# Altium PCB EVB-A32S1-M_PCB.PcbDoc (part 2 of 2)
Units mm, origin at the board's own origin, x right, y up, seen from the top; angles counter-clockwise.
Board outline 134 x 65 mm, 4 copper layers (L1 (Signal), L2 (GND), L3 (PWR), L4 (Signal)), stack 1.566 mm thick; 111 components, 86 nets, 414 pads, 364 vias.

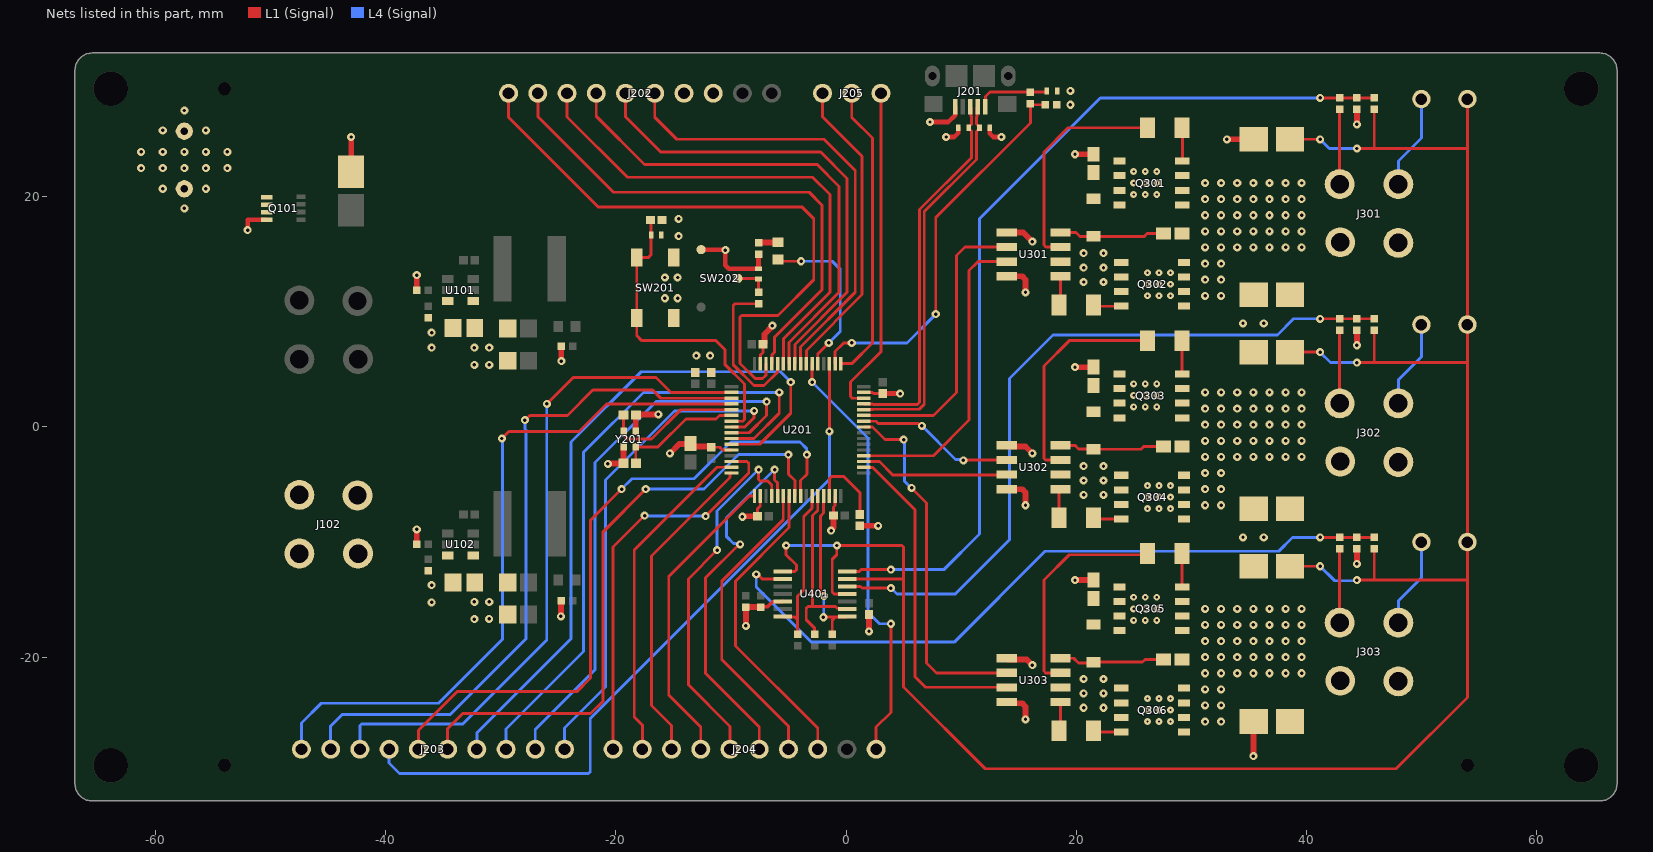
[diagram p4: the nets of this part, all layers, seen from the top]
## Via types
v1: diameter 0.7, hole 0.3, L1 (Signal) to L4 (Signal), tented both sides, 162 vias
v2: diameter 0.7, hole 0.3, L1 (Signal) to L4 (Signal), tented top, 144 vias
v3: diameter 0.6, hole 0.2, L1 (Signal) to L4 (Signal), tented top, 54 vias
v4: diameter 0.6, hole 0.2, L1 (Signal) to L4 (Signal), tented both sides, 4 vias

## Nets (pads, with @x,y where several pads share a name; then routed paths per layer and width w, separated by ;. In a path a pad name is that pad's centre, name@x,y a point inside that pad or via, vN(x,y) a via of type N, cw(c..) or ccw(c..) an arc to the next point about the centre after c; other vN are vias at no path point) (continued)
+VCC: C101.2 C105.2 C109.1 C301.2 C303.2 C305.2 D301.2 D302.2 D303.2 Q101.1 Q101.2 Q101.3 Q301.5 Q301.6 Q301.7 Q301.8 Q303.5 Q303.6 Q303.7 Q303.8 Q305.5 Q305.6 Q305.7 Q305.8 R101.2 R104.2 U101.3 U102.3 U301.1 U302.1 U303.1 | length 7.6
  L1 (Signal) w0.5: U303.1@13.96,-20.095 14.07,-20.205 15.705,-20.205 v1(16.2,-20.7) ; U302.1@13.96,-1.595 14.07,-1.705 15.605,-1.705 v1(16.2,-2.3) ; U301.1@13.96,16.905 15.395,16.905 v1(16.2,16.1)
  other v1: -36,-15.25 -36,-13.75 -36,6.9 -36,8.2 -57.5,19 -59.375,20.7 -55.625,20.7 -61.25,22.5 -59.375,22.5 -57.5,22.5 -55.625,22.5 -53.75,22.5 -61.25,23.9 -59.375,23.9 -57.5,23.9 -55.625,23.9 -53.75,23.9 -59.375,25.78 -55.625,25.78 -57.5,27.5
  other v3: 25,-16.8 26,-16.8 27,-16.8 25,-15.8 26,-15.8 27,-15.8 25,-14.8 26,-14.8 27,-14.8 25,1.75 26,1.75 27,1.75 25,2.75 26,2.75 27,2.75 25,3.75 26,3.75 27,3.75 25,20.2 26,20.2 27,20.2 25,21.2 26,21.2 27,21.2 25,22.2 26,22.2 27,22.2
BEMF_A: R406.2 R411.2 R412.1 U401.7 | length 78.9
  L1 (Signal) w0.25: U401.7@0.1,-12.55 1.154,-12.55 1.304,-12.4 v1(3.9,-12.4) ; v1(41.2,28.6) R412.1@42.9,28.6 R411.2@44.4,28.6 R406.2@45.9,28.6
  L4 (Signal) w0.25: v1(3.9,-12.4) 8.5,-12.4 11.6,-9.3 11.6,18.1 22.1,28.6 v1(41.2,28.6)
BEMF_B: R407.2 R410.2 R413.1 U401.5 | length 64.2
  L1 (Signal) w0.25: U401.5@0.1,-13.85 1.249,-13.85 1.399,-14 v1(3.9,-14) ; v1(41.2,9.4) R413.1@42.9,9.4 R410.2@44.4,9.4 R407.2@45.9,9.4
  L4 (Signal) w0.25: v1(3.9,-14) 3.925,-14 4.425,-14.5 9.5,-14.5 14.2,-9.8 14.2,4.2 18,8 37.5,8 38.9,9.4 v1(41.2,9.4)
BEMF_C: R408.2 R409.2 R414.1 U401.9 | length 63
  L1 (Signal) w0.25: v1(-7.8,-12.8) -7.678,-12.8 -7.278,-13.2 U401.9@-5.5,-13.2 ; v1(41.2,-9.6) R414.1@42.9,-9.6 ; R414.1@42.9,-9.6 R409.2@44.4,-9.6 R408.2@45.9,-9.6
  L4 (Signal) w0.25: v1(-7.8,-12.8) -7.8,-13.9 -3,-18.7 9.4,-18.7 17.3,-10.8 37.6,-10.8 38.8,-9.6 v1(41.2,-9.6)
BOOT0: R201.2 U201.60 | length 13.3
  L1 (Signal) w0.25: R201.2@-7.588,10.712 -9.654,10.712 -9.8,10.566 -9.8,5.4 -8,3.6 -7.112,3.6 -5.955,4.757 -5.955,5.495 U201.60@-5.95,5.5
COM: D401.1 D402.1 D403.1 R406.1 R407.1 R408.1 TP401.1 TP402.1 TP403.1 U401.4 U401.6 U401.8 | length 199.6
  L1 (Signal) w0.25: U401.8@-5.5,-12.55 -4.446,-12.55 -4.3,-12.404 -4.3,-12 -5.2,-11.1 v1(-5.2,-10.3) ; U401.4@0.1,-14.5 -1.054,-14.5 -1.2,-14.354 -1.2,-11.5 -0.8,-11.1 v1(-0.8,-10.3) 4.854,-10.3 5,-10.446 5,-13.2 5,-22.6 12.1,-29.7 47.8,-29.7 54,-23.5 54,-13.154 ; U401.6@0.1,-13.2 4.854,-13.2 4.954,-13.2 ; D403.1@38.575,-12.1 v1(41.2,-12.1) ; D402.1@38.575,6.5 v1(41.2,6.5) ; D401.1@38.575,25 v1(41.2,25) ; v1(44.4,-13.3) 45.9,-13.3 ; v1(44.4,5.6) 45.9,5.6 ; v1(44.4,24.2) 45.9,24.2 ; R408.1@45.9,-10.6 45.9,-13.3 ; R407.1@45.9,8.4 45.9,5.6 ; R406.1@45.9,27.6 45.9,24.2 ; TP403.1@54,28.5 54,24.2 ; 45.9,-13.3 53.854,-13.3 54,-13.154 ; 45.9,5.6 54,5.6 ; 45.9,24.2 54,24.2 ; 54,-13.154 TP401.1@54,-10 54,5.6 ; 54,5.6 TP402.1@54,8.9 54,24.2
  L4 (Signal) w0.25: v1(-5.2,-10.3) v1(-0.8,-10.3) ; v1(41.2,-12.1) 42.464,-13.364 44.336,-13.364 v1(44.4,-13.3) ; v1(41.2,6.5) 42.1,5.6 v1(44.4,5.6) ; v1(41.2,25) 42,24.2 v1(44.4,24.2)
GHO_A: Q301.4 R301.2 | length 2.9
  L1 (Signal) w0.25: Q301.4@29.235,23.105 R301.2@29.235,26
  L1 (Signal) w0.5: R301.2@29.2,26 R301.2@29.235,26
GHO_B: Q303.4 R303.2 | length 2.9
  L1 (Signal) w0.25: R303.2@29.2,7.5 29.2,4.605 Q303.4@29.235,4.605
GHO_C: Q305.4 R305.2 | length 2.9
  L1 (Signal) w0.25: R305.2@29.2,-11 29.2,-13.86 Q305.4@29.235,-13.895
GLO_A: Q302.4 R302.2 | length 2.5
  L1 (Signal) w0.25: R302.2@21.5,10.495 Q302.4@23.915,10.495
  L1 (Signal) w0.5: R302.2@21.5,10.495 R302.2@21.5,10.6
GLO_B: Q304.4 R304.2 | length 2.5
  L1 (Signal) w0.25: R304.2@21.5,-7.9 21.605,-8.005 Q304.4@23.915,-8.005
GLO_C: Q306.4 R306.2 | length 2.5
  L1 (Signal) w0.25: R306.2@21.5,-26.4 21.605,-26.505 Q306.4@23.915,-26.505
GND: C101.1 C103.1 C104.1 C105.1 C107.1 C108.1 C109.2 C201.1 C202.1 C203.1 C204.1 C205.1 C206.1 C207.1 C208.1 C209.1 C210.1 C211.1 C212.1 C301.1 C303.1 C305.1 C401.1 D103.2 D201.2 D202.2 D204.2 D205.2 D206.2 D304.2 D305.2 D306.2 D401.2 D402.2 D403.2 J102.1 J102.2 J102.3 J102.4 J201.5 J202.3 J202.4 Q101.4 Q302.1 Q302.2 Q302.3 Q304.1 Q304.2 Q304.3 Q306.1 Q306.2 Q306.3 R102.1 R103.1 R105.1 R106.1 R202.1 R203.1 R404.1 R405.1 R409.1 R410.1 R411.1 SW201.3 SW201.4 SW202.1 U101.4 U102.4 U201.12 U201.18 U201.31 U201.47 U201.63 U301.4 U302.4 U303.4 U401.12 Y201.2 Y201.4 | length 81.2
  L1 (Signal) w0.25: C202.1@-11.7,-1.76 -10.965,-1.76 -10.73,-1.995 -9.955,-1.995 U201.12@-9.95,-2 ; C204.1@-7.69,-7.75 -7.69,-7.11 -7.455,-6.875 -7.455,-6.005 U201.18@-7.45,-6 ; U201.63@-7.45,5.5 -7.445,5.505 -7.445,6.243 -7.21,6.478 C205.1@-7.21,7.2 ; C206.1@-1.09,-7.7 -1.09,-6.965 -0.955,-6.83 -0.955,-6.005 U201.31@-0.95,-6 ; U201.47@1.55,3 1.555,2.995 2.293,2.995 2.378,2.91 C207.1@3.2,2.91
  L1 (Signal) w0.3: R404.1@-7.4,-15.65 -7.352,-15.602 -6.801,-15.602 -6.373,-15.175 -5.525,-15.175 U401.12@-5.5,-15.15
  L1 (Signal) w0.4: v1(-52,17.1) -52,17.995 Q101.4@-50.335,17.995 ; SW202.1@-12.588,15.412 -12.563,15.387 v1@-10.513,15.387 ; v1(-10.488,15.362) -10.488,14.055 -10.195,13.762 D202.2@-7.6,13.762 ; R202.1@-7.6,15 D202.2@-7.6,13.762 ; D202.2@-7.588,13.762 D202.2@-7.6,13.762 ; C207.1@3.2,2.91 4.7,2.91 v1(4.7,2.9) ; v1(7.3,26.5) 8.9,26.5 9.5,27.1 J201.5@9.5,27.825 ; v1(8.7,25.2) 9.4,25.2 9.75,25.55 D206.2@9.75,26 ; D205.2@12.5,26 12.5,25.5 12.8,25.2 v1(13.5,25.2)
  L1 (Signal) w0.5: D103.2@-43,22.175 v1(-43,25.2) ; R105.1@-37.3,-10.2 v1(-37.3,-8.9) ; R102.1@-37.3,11.9 v1(-37.3,13.2) ; v1(-24.775,-16.45) -24.762,-16.437 -24.762,-15.112 R106.1@-24.75,-15.1 ; R103.1@-24.75,7 -24.75,5.725 v1(-24.725,5.725) ; v1(-20.7,-3.2) -20.675,-3.175 -19.375,-3.175 C211.1@-19.35,-3.15 -19.337,-3.138 -19.337,-1.737 Y201.2@-19.325,-1.725 ; Y201.4@-18.275,-0.375 -18.262,-0.363 -18.262,1.038 C210.1@-18.25,1.05 -18.225,1.075 -16.325,1.075 v1(-16.3,1.1) ; v1(-15.3,-2.3) -14.482,-1.482 -13.532,-1.482 C201.1@-13.5,-1.45 -13.25,-1.7 -11.76,-1.7 C202.1@-11.7,-1.76 ; v1(-9,-7.8) -9,-7.75 C204.1@-7.69,-7.75 ; v1(-8.7,-17.275) R405.1@-8.7,-15.65 R404.1@-7.4,-15.65 ; C205.1@-7.21,7.2 -7.1,7.31 -7.08,7.31 -7.08,8.066 -6.4,8.746 v1(-6.4,8.8) ; v1(-1.3,-9) -1.3,-8.946 -1.09,-8.736 C206.1@-1.09,-7.7 ; C212.1@1.2,-8.59 2.8,-8.59 v1(2.8,-8.6) ; v1(2,-17.765) C401.1@2,-16.29 ; U303.4@13.96,-23.905 14.07,-24.015 15.307,-24.015 15.6,-24.308 v1(15.6,-25.4) ; U302.4@13.96,-5.405 15.307,-5.405 15.6,-5.698 v1(15.6,-6.8) ; U301.4@13.96,13.095 15.307,13.095 15.6,12.802 v1(15.6,11.7) ; v1(19.9,-13.3) C305.1@21.5,-13.3 ; v1(19.9,5.2) C303.1@21.5,5.2 ; v1(19.9,23.7) C301.1@21.5,23.7 ; v1(33.1,25) D401.2@35.425,25 ; v1(35.4,-28.6) 35.4,-25.625 D306.2@35.425,-25.6 ; v1(44.4,-11.9) R409.1@44.4,-10.6 ; v1(44.4,7.1) R410.1@44.4,8.4 ; v1(44.4,26.3) R411.1@44.4,27.6
  other v1: 22.375,-24.4 22.375,-23.15 22.375,-21.9 -32.3,-16.7 -31.02,-16.68 -32.3,-15.2 -31,-15.2 34.5,-9.6 36.3,-9.6 22.375,-5.9 22.375,-4.65 22.375,-3.4 -32.3,5.4 -31,5.4 -13,6.2 -11.8,6.2 -32.3,6.9 -31,6.9 34.5,9 36.3,9 -15.738,11.188 -14.638,11.188 22.375,12.6 -15.738,12.988 -14.638,12.988 22.375,13.85 22.375,15.1 -14.538,16.588 -14.538,18.088 19.5,28 19.5,29.2
HIN_A: U201.43 U301.2 | length 25.4
  L1 (Signal) w0.25: U201.43@1.55,1 7.6,1 9.6,3 9.6,14.9 10.335,15.635 U301.2@13.96,15.635
HIN_B: U201.42 U302.2 | length 13.8
  L1 (Signal) w0.25: U201.42@1.55,0.5 2.6,0.5 2.8,0.3 6.278,0.3 6.478,0.1 v1(6.6,0.1) ; v1(10.2,-2.9) 10.218,-2.882 13.942,-2.882 U302.2@13.96,-2.865
  L4 (Signal) w0.25: v1(6.6,0.1) 9.514,-2.814 10.114,-2.814 v1(10.2,-2.9)
HIN_C: U201.41 U303.2 | length 31.5
  L1 (Signal) w0.25: U201.41@1.555,-0.005 2.293,-0.005 3.388,-1.1 v1(5,-1.1) ; v1(5.7,-5.3) 7,-6.6 7,-20.5 7.865,-21.365 U303.2@13.96,-21.365
  L4 (Signal) w0.25: v1(5,-1.1) 5.085,-1.185 5.085,-4.713 5.672,-5.3 v1(5.7,-5.3)
HO_A: R301.1 U301.7 | length 19.5
  L1 (Signal) w0.25: U301.7@18.64,15.635 17.365,15.635 17.2,15.8 17.2,23.9 19.3,26 R301.1@26.2,26
HO_B: R303.1 U302.7 | length 19.4
  L1 (Signal) w0.25: U302.7@18.64,-2.865 17.346,-2.865 17.2,-2.719 17.2,5.3 19.4,7.5 R303.1@26.2,7.5
HO_C: R305.1 U303.7 | length 19.1
  L1 (Signal) w0.25: U303.7@18.64,-21.365 17.346,-21.365 17.2,-21.219 17.2,-13.3 19.4,-11.1 R305.1@26,-11.1
LIN_A: U201.36 U301.3 | length 27
  L1 (Signal) w0.25: U201.36@1.55,-2.5 7.6,-2.5 10.7,0.6 10.7,9.7 10.7,13.6 11.465,14.365 U301.3@13.96,14.365
LIN_B: U201.35 U302.3 | length 12.9
  L1 (Signal) w0.25: U201.35@1.55,-3 2.9,-3 4.067,-4.167 13.927,-4.167 U302.3@13.96,-4.135
LIN_C: U201.34 U303.3 | length 28.8
  L1 (Signal) w0.25: U201.34@1.55,-3.5 1.555,-3.505 2.305,-3.505 6,-7.2 6,-21.7 6.917,-22.617 13.942,-22.617 U303.3@13.96,-22.635
LO_A: R302.1 U301.5 | length 2.6
  L1 (Signal) w0.25: R302.1@18.5,10.6 18.64,10.6 U301.5@18.64,13.095
LO_B: R304.1 U302.5 | length 2.6
  L1 (Signal) w0.25: R304.1@18.5,-7.9 18.5,-5.545 U302.5@18.64,-5.405
LO_C: R306.1 U303.5 | length 2.6
  L1 (Signal) w0.25: R306.1@18.5,-26.4 18.64,-26.26 U303.5@18.64,-23.905
NRST: C209.2 D201.1 SW201.1 SW201.2 U201.7 | length 27.3
  L1 (Signal) w0.25: C209.2@-16.978,17.988 -16.938,17.948 D201.1@-16.938,16.688 -16.938,14.962 -17.187,14.713 SW201.2@-18.188,14.713 SW201.1@-18.188,9.463 -18.188,7.946 -17.741,7.5 -11.3,7.5 -10.5,6.7 -10.5,5.4 -8.829,3.729 -8.829,0.646 -8.975,0.5 U201.7@-9.95,0.5
OSC_IN: C210.2 U201.5 Y201.1 | length 12.4
  L1 (Signal) w0.25: C210.2@-19.35,1.05 -19.325,1.025 Y201.1@-19.325,-0.375 -19.218,-0.482 -19.218,-0.909 -19.072,-1.055 -16.909,-1.055 -14.354,1.5 U201.5@-9.95,1.5
OSC_OUT: C211.2 U201.6 Y201.3 | length 10.9
  L1 (Signal) w0.25: C211.2@-18.25,-3.15 -18.275,-3.125 Y201.3@-18.275,-1.725 -16.325,-1.725 -13.9,0.7 -11.3,0.7 -11,1 U201.6@-9.95,1
PA0: J204.1 U201.14 | length 34.5
  L1 (Signal) w0.25: J204.1@-20.24,-28 -20.24,-10.44 v1(-17.5,-7.7) ; v1(-12.2,-7.75) -8.446,-3.996 -8.446,-3.146 -8.593,-3 U201.14@-9.95,-3
  L4 (Signal) w0.25: v1(-17.5,-7.7) -17.475,-7.725 -12.225,-7.725 v1(-12.2,-7.75)
PA1: J204.2 U201.15 | length 29
  L1 (Signal) w0.25: J204.2@-17.7,-28 -17.7,-25.9 -18.4,-25.2 -18.4,-10.7 -11.2,-3.5 U201.15@-9.95,-3.5
PA2: J204.3 U201.16 | length 27.7
  L1 (Signal) w0.25: J204.3@-15.16,-28 -15.16,-25.94 -16.9,-24.2 -16.9,-11.2 -10.079,-4.379 -10.079,-4.025 -10.054,-4 U201.16@-9.95,-4
PA3: J204.4 U201.17 | length 26.5
  L1 (Signal) w0.25: J204.4@-12.62,-28 -12.62,-26.08 -15.4,-23.3 -15.4,-13 -8.4,-6 U201.17@-7.95,-6
PA4: J204.5 U201.20 | length 31.4
  L1 (Signal) w0.25: v1(-11.2,-10.7) -13.7,-13.2 -13.7,-22.4 -10.08,-26.02 J204.5@-10.08,-28 ; v1@-7.6,-3.8 -7.6,-4.554 -7.454,-4.7 -6.8,-4.7 -6.455,-5.045 -6.455,-5.995 U201.20@-6.45,-6
  L4 (Signal) w0.25: v1(-11.2,-10.7) -11.2,-7.3 v1(-7.6,-3.7)
PA5: J204.6 U201.21 | length 32.5
  L1 (Signal) w0.25: v1(-9.2,-10.2) -9.3,-10.2 -12.2,-13.1 -12.2,-21.4 -7.54,-26.06 J204.6@-7.54,-28 ; v1(-6.2,-3.7) -6.2,-4.6 -5.95,-4.85 U201.21@-5.95,-6
  L4 (Signal) w0.25: v1(-9.2,-10.2) -9.286,-10.114 -9.786,-10.114 -10.4,-9.5 -10.4,-7.9 v1(-6.2,-3.7)
PA6: J204.7 U201.22 | length 26.6
  L1 (Signal) w0.25: U201.22@-5.45,-6 -5.455,-6.005 -5.455,-8.055 -10.8,-13.4 -10.8,-20.2 -5,-26 J204.7@-5,-28
PA7: J204.8 U201.23 | length 26.9
  L1 (Signal) w0.25: U201.23@-4.945,-5.995 U201.23@-4.95,-6 -4.945,-6.005 -4.945,-8.745 -9.6,-13.4 -9.6,-19.02 -2.46,-26.16 J204.8@-2.46,-28
PB4: J202.5 U201.56 | length 40.2
  L1 (Signal) w0.25: J202.5@-16.62,29 -16.62,26.92 -14.7,25 -1.9,25 0.8,22.3 0.8,11.7 -3.95,6.95 U201.56@-3.95,5.5
PB5: J202.6 U201.57 | length 41.5
  L1 (Signal) w0.25: J202.6@-19.16,29 -19.16,26.96 -16.1,23.9 -2.2,23.9 0.1,21.6 0.1,11.7 -4.445,7.155 -4.445,5.505 U201.57@-4.45,5.5
PB6: J202.7 U201.58 | length 42.8
  L1 (Signal) w0.25: J202.7@-21.7,29 -21.7,27 -17.5,22.8 -2.5,22.8 -0.6,20.9 -0.6,11.7 -4.945,7.355 -4.945,5.505 U201.58@-4.95,5.5
PB7: J202.8 U201.59 | length 44.1
  L1 (Signal) w0.25: J202.8@-24.24,29 -24.24,26.94 -19,21.7 -2.9,21.7 -1.4,20.2 -1.4,11.7 -5.445,7.655 -5.445,5.505 U201.59@-5.45,5.5
PB8: J202.9 U201.61 | length 45.5
  L1 (Signal) w0.25: J202.9@-26.78,29 -26.78,26.98 -20.2,20.4 -3.2,20.4 -2.1,19.3 -2.1,11.9 -6.2,7.8 -6.2,6.488 -6.445,6.243 -6.445,5.505 U201.61@-6.45,5.5
PB9: J202.10 U201.62 | length 53.3
  L1 (Signal) w0.25: J202.10@-29.32,29 -29.32,26.92 -21.5,19.1 -3.8,19.1 -2.8,18.1 -2.8,12.8 -5.9,9.7 -9.054,9.7 -9.2,9.554 -9.2,5.512 -7.888,4.2 -7.246,4.2 -6.95,4.496 U201.62@-6.95,5.5
PC0: J203.1 U201.8 | length 43.2
  L1 (Signal) w0.25: U201.8@-9.95,0 -9.945,0.005 -8.795,0.005 -7.978,0.822 v1(-7.978,1.4)
  L4 (Signal) w0.25: J203.1@-24.46,-28 -24.46,-26.16 -20.9,-22.6 -20.9,-4.6 -14.9,1.4 v1(-7.978,1.4)
PC1: J203.2 U201.9 | length 49
  L1 (Signal) w0.25: U201.9@-9.95,-0.5 -8.4,-0.5 -6.9,1 v1(-6.9,2.2)
  L4 (Signal) w0.25: J203.2@-27,-28 -27,-26.3 -21.8,-21.1 -21.8,-3.1 -16.5,2.2 v1(-6.9,2.2)
PC2: J203.3 U201.10 | length 54.6
  L1 (Signal) w0.25: U201.10@-9.95,-1 -8,-1 -5.8,1.2 v1(-5.8,3)
  L4 (Signal) w0.25: J203.3@-29.54,-28 -29.54,-26.24 -22.8,-19.5 -22.8,-2.2 -17.6,3 v1(-5.8,3)
PC3: J203.4 U201.11 | length 61.1
  L1 (Signal) w0.25: U201.11@-9.95,-1.5 -7.5,-1.5 -4.8,1.2 v1(-4.8,3.9)
  L4 (Signal) w0.25: J203.4@-32.08,-28 -32.08,-26.58 -23.9,-18.4 -23.9,-1.3 -17.8,4.8 -5.7,4.8 v1(-4.8,3.9)
PC4: J203.5 U201.24 | length 53.7
  L1 (Signal) w0.25: J203.5@-34.62,-28 -34.62,-26.22 -33.3,-24.9 -22.2,-24.9 -21.1,-23.8 -21.1,-9.1 v1(-17.4,-5.4) ; v1(-5,-2.4) -5,-4.1 -4.445,-4.655 -4.445,-5.995 U201.24@-4.45,-6
  L4 (Signal) w0.25: v1(-17.4,-5.4) -12.335,-5.4 -9.335,-2.4 v1(-5,-2.4)
PC5: J203.6 U201.25 | length 58.4
  L1 (Signal) w0.25: J203.6@-37.16,-28 -37.16,-26.36 -33.8,-23 -23.4,-23 -22.2,-21.8 -22.2,-8.1 v1(-19.5,-5.4) ; U201.25@-3.95,-6 -3.945,-5.995 -3.945,-4.645 -3.4,-4.1 v1(-3.4,-2.4)
  L4 (Signal) w0.25: v1(-19.5,-5.4) -18.6,-4.5 -13.2,-4.5 -10,-1.3 -4,-1.3 -3.413,-1.887 -3.413,-2.387 v1(-3.4,-2.4)
PC10: J203.7 U201.51 | length 63.2
  L1 (Signal) w0.25: v1(-1.45,-0.38) U201.51@-1.45,5.5
  L4 (Signal) w0.25: J203.7@-39.7,-28 -39.7,-29.2 -38.8,-30.1 -22.371,-30.1 -22.225,-29.954 -22.225,-25.325 -1.45,-4.55 v1(-1.45,-0.38)
PC13: J203.8 U201.2 | length 59.4
  L1 (Signal) w0.25: v1(-26,2) -23.7,4.3 -16.5,4.3 -15.205,3.005 -9.955,3.005 U201.2@-9.95,3
  L4 (Signal) w0.25: J203.8@-42.24,-28 -42.24,-25.946 -42.094,-25.8 -33.3,-25.8 -26,-18.5 v1(-26,2)
PC14: J203.9 U201.3 | length 60.5
  L1 (Signal) w0.25: v1(-27.9,0.6) -27.875,0.6 -27.475,1 -24.2,1 -22,3.2 -16.8,3.2 -16.1,2.5 U201.3@-9.95,2.5
  L4 (Signal) w0.25: J203.9@-44.78,-28 -44.78,-25.98 -43.8,-25 -34.4,-25 -27.8,-18.4 -27.8,-0.25 -27.9,-0.15 v1(-27.9,0.6)
PC15: J203.10 U201.4 | length 61.4
  L1 (Signal) w0.25: v1(-29.9,-1) -29.3,-0.4 -23.2,-0.4 -20.8,2 U201.4@-9.95,2
  L4 (Signal) w0.25: J203.10@-47.32,-28 -47.32,-25.72 -45.602,-24.002 -35.402,-24.002 -29.85,-18.45 -29.85,-1.05 v1(-29.9,-1)
PD2: J204.10 U201.54 | length 37.5
  L1 (Signal) w0.25: U201.54@-2.95,5.5 -2.95,3.95 v1@-2.9,3.9 ; J204.10@2.62,-28 2.62,-26.08 3.9,-24.8 v1(3.9,-17.1)
  L4 (Signal) w0.25: v1(-2.95,3.9) 1.9,-0.95 1.9,-16.1 2.9,-17.1 v1(3.9,-17.1)
PHASE_A: C302.1 D304.1 J301.1 J301.2 J301.3 J301.4 Q301.1 Q301.2 Q301.3 Q302.5 Q302.6 Q302.7 Q302.8 R412.2 TP301.1 U301.6 | length 14.7
  L1 (Signal) w0.25: J301.4@42.9,21.1 R412.2@42.9,27.6
  L4 (Signal) w0.25: J301.3@48,21.1 48,23.1 50,25.1 TP301.1@50,28.5
  other v1: 20.65,12.6 20.65,13.85 20.65,15.1
  other v2: 31.2,11.4 32.6,11.4 31.2,12.8 32.6,12.8 31.2,14.2 32.6,14.2 31.2,15.6 32.6,15.6 34,15.6 35.4,15.6 36.8,15.6 38.2,15.6 39.6,15.6 31.2,17 32.6,17 34,17 35.4,17 36.8,17 38.2,17 39.6,17 31.2,18.4 32.6,18.4 34,18.4 35.4,18.4 36.8,18.4 38.2,18.4 39.6,18.4 31.2,19.8 32.6,19.8 34,19.8 35.4,19.8 36.8,19.8 38.2,19.8 39.6,19.8 31.2,21.2 32.6,21.2 34,21.2 35.4,21.2 36.8,21.2 38.2,21.2 39.6,21.2
  other v3: 26.2,11.4 27.2,11.4 28.2,11.4 26.2,12.4 27.2,12.4 28.2,12.4 26.2,13.4 27.2,13.4 28.2,13.4
PHASE_B: C304.1 D305.1 J302.1 J302.2 J302.3 J302.4 Q303.1 Q303.2 Q303.3 Q304.5 Q304.6 Q304.7 Q304.8 R413.2 TP302.1 U302.6 | length 14
  L1 (Signal) w0.25: J302.4@42.9,2.05 R413.2@42.9,8.4
  L4 (Signal) w0.25: J302.3@48,2.05 48,4.1 50,6.1 TP302.1@50,8.9
  other v1: 20.65,-5.9 20.65,-4.65 20.65,-3.4
  other v2: 31.2,-6.8 32.6,-6.8 31.2,-5.4 32.6,-5.4 31.2,-4 32.6,-4 31.2,-2.6 32.6,-2.6 34,-2.6 35.4,-2.6 36.8,-2.6 38.2,-2.6 39.6,-2.6 31.2,-1.2 32.6,-1.2 34,-1.2 35.4,-1.2 36.8,-1.2 38.2,-1.2 39.6,-1.2 31.2,0.2 32.6,0.2 34,0.2 35.4,0.2 36.8,0.2 38.2,0.2 39.6,0.2 31.2,1.6 32.6,1.6 34,1.6 35.4,1.6 36.8,1.6 38.2,1.6 39.6,1.6 31.2,3 32.6,3 34,3 35.4,3 36.8,3 38.2,3 39.6,3
  other v3: 26.2,-7.1 27.2,-7.1 28.2,-7.1 26.2,-6.1 27.2,-6.1 28.2,-6.1 26.2,-5.1 27.2,-5.1 28.2,-5.1
PHASE_C: C306.1 D306.1 J303.1 J303.2 J303.3 J303.4 Q305.1 Q305.2 Q305.3 Q306.5 Q306.6 Q306.7 Q306.8 R414.2 TP303.1 U303.6 | length 14.2
  L1 (Signal) w0.25: J303.4@42.9,-17 R414.2@42.9,-10.6
  L4 (Signal) w0.25: J303.3@48,-17 48,-15.1 50,-13.1 TP303.1@50,-10
  other v1: 20.65,-24.4 20.65,-23.15 20.65,-21.9
  other v2: 31.2,-25.6 32.6,-25.6 31.2,-24.2 32.6,-24.2 31.2,-22.8 32.6,-22.8 31.2,-21.4 32.6,-21.4 34,-21.4 35.4,-21.4 36.8,-21.4 38.2,-21.4 39.6,-21.4 31.2,-20 32.6,-20 34,-20 35.4,-20 36.8,-20 38.2,-20 39.6,-20 31.2,-18.6 32.6,-18.6 34,-18.6 35.4,-18.6 36.8,-18.6 38.2,-18.6 39.6,-18.6 31.2,-17.2 32.6,-17.2 34,-17.2 35.4,-17.2 36.8,-17.2 38.2,-17.2 39.6,-17.2 31.2,-15.8 32.6,-15.8 34,-15.8 35.4,-15.8 36.8,-15.8 38.2,-15.8 39.6,-15.8
  other v3: 26.2,-25.6 27.2,-25.6 28.2,-25.6 26.2,-24.6 27.2,-24.6 28.2,-24.6 26.2,-23.6 27.2,-23.6 28.2,-23.6
PROG_LED: D203.2 U201.53 | length 14.8
  L1 (Signal) w0.25: D203.2@-5.9,14.55 -5.75,14.4 v1(-3.9,14.4) ; U201.53@-2.45,5.5 -2.45,6.35 v1(-1.5,7.3)
  L4 (Signal) w0.25: v1(-3.9,14.4) -1.2,14.4 -0.5,13.7 -0.5,8.3 v1(-1.5,7.3)
PROG_LED_K: D203.1 R202.2 | length 1.7
  L1 (Signal) w0.5: R202.2@-7.6,16 -7.575,16.025 -5.925,16.025 D203.1@-5.9,16.05
SENSE_A: R401.1 U201.29 U401.1 | length 14.5
  L1 (Signal) w0.25: v1(-1.965,-16.535) -1.93,-16.5 -0.9,-16.5 ; U201.29@-1.95,-6 -1.955,-6.005 -1.955,-7.478 -2.2,-7.723 -2.2,-14.33 -1.907,-14.624 v1(-1.907,-14.702) ; R401.1@-1.2,-18 -1.2,-17.4 -1.2,-16.8 -0.9,-16.5 ; U401.1@0.1,-16.45 0.05,-16.5 -0.9,-16.5
  L4 (Signal) w0.25: v1(-1.965,-16.535) -1.933,-16.502 -1.933,-14.728 v1(-1.907,-14.702)
SENSE_B: R402.1 U201.28 U401.2 | length 15.9
  L1 (Signal) w0.25: -2.9,-15.5 -2.9,-7.7 -2.455,-7.255 -2.455,-6.005 U201.28@-2.45,-6 ; R402.1@-2.7,-18 -2.754,-17.946 -2.754,-17.446 -3.451,-16.749 -3.451,-15.744 -3.305,-15.598 -2.9,-15.598 -0.915,-15.598 -0.763,-15.75 0.05,-15.75 U401.2@0.1,-15.8
SENSE_C: R403.1 U201.27 U401.14 | length 13.9
  L1 (Signal) w0.25: U401.14@-5.5,-16.45 -5.45,-16.5 -4.446,-16.5 -4.2,-16.746 ; R403.1@-4.2,-18 -4.2,-16.746 ; U201.27@-2.95,-6 -2.955,-6.005 -2.955,-7.055 -3.67,-7.77 -3.67,-14.151 -4.2,-14.681 -4.2,-16.746
SW_BOOT0: D202.1 R201.1 SW202.2 | length 3
  L1 (Signal) w0.25: SW202.2@-9.388,12.912 -7.588,12.912 D202.1@-7.588,12.862 R201.1@-7.588,11.712
SW_CLK: J205.2 U201.49 | length 25.9
  L1 (Signal) w0.25: U201.49@-0.45,5.5 0.5,5.5 2.3,7.3 2.3,25.1 0.5,26.9 J205.2@0.5,29
SW_IO: J205.1 U201.46 | length 28.7
  L1 (Signal) w0.25: U201.46@1.55,2.5 0.546,2.5 0.4,2.646 0.4,3.9 3.04,6.54 J205.1@3.04,29
SW_O: J205.3 U201.55 | length 26.9
  L1 (Signal) w0.25: U201.55@-3.45,5.5 -3.445,5.505 -3.445,6.655 1.4,11.5 1.4,23.52 -2.04,26.96 J205.3@-2.04,29
USB_D_N: D205.1 J201.2 U201.44 | length 33.5
  L1 (Signal) w0.25: U201.44@1.55,1.5 1.555,1.505 2.293,1.505 2.333,1.545 6.368,1.545 6.8,1.977 6.8,18.72 11.33,23.25 11.33,25.679 11.476,25.825 11.525,25.825 11.6,25.9 D205.1@11.6,26 11.6,26.1 11.525,26.175 11.476,26.175 11.33,26.321 11.33,26.95 11.375,26.995 11.375,27.75 J201.2@11.45,27.825
USB_D_P: D206.1 J201.3 U201.45 | length 32.8
  L1 (Signal) w0.25: U201.45@1.55,2 1.555,1.995 2.293,1.995 2.333,1.955 6.199,1.955 6.39,2.146 6.39,18.89 10.92,23.42 10.92,25.679 10.774,25.825 10.725,25.825 10.65,25.9 D206.1@10.65,26 10.65,26.1 10.725,26.175 10.774,26.175 10.92,26.321 10.92,26.95 10.875,26.995 10.875,27.75 J201.3@10.8,27.825
VB_A: C302.2 D301.1 U301.8 | length 9.2
  L1 (Signal) w0.25: U301.8@18.64,16.905 19.995,16.905 20.335,16.565 D301.1@21.5,16.565 25.915,16.565 26.15,16.8 C302.2@27.6,16.8
VB_B: C304.2 D302.1 U302.8 | length 9.2
  L1 (Signal) w0.25: U302.8@18.64,-1.595 19.895,-1.595 20.2,-1.9 21.465,-1.9 D302.1@21.5,-1.935 25.635,-1.935 25.87,-1.7 C304.2@27.6,-1.7
VB_C: C306.2 D303.1 U303.8 | length 9.3
  L1 (Signal) w0.25: U303.8@18.64,-20.095 19.795,-20.095 20.2,-20.5 21.435,-20.5 D303.1@21.5,-20.435 25.765,-20.435 26,-20.2 C306.2@27.6,-20.2
VBUS: D204.1 J201.1 R204.2 | length 6.5
  L1 (Signal) w0.25: J201.1@12.1,27.825 12.115,27.84 12.115,28.715 12.5,29.1 R204.2@16.025,29.1 17.45,29.1 D204.1@17.45,29.2
VBUS_SENSE: R203.2 R204.1 U201.50 | length 34.2
  L1 (Signal) w0.25: U201.50@-0.95,5.5 -0.945,5.505 -0.945,6.555 -0.2,7.3 v1(0.5,7.3) ; v1(7.8,9.8) 7.8,18.2 16.025,26.425 R204.1@16.025,28.1 R204.1@16.215,27.91 ; R204.1@16.215,28 R203.2@17.325,28
  L4 (Signal) w0.25: v1(0.5,7.3) 5.3,7.3 v1(7.8,9.8)
VCAP: C212.2 U201.30 | length 6.8
  L1 (Signal) w0.25: U201.30@-1.45,-6 -1.45,-4.496 -1.254,-4.3 -0.2,-4.3 1.21,-5.71 C212.2@1.21,-7.7
pads on no net: J201.4 J201.6 J201.7 J201.8 J201.9 J201.10 J201.11 J204.9 U201.26 U201.33 U201.37 U201.38 U201.39 U201.40 U201.52 U401.13

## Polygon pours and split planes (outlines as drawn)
+VCC on L1 (Signal) "+VCC_L01_P008" (solid, pour order 8): -35.129,7.495 -35.205,7.495 -35.205,6.25 -36.75,6.25 -36.75,9.9 -35.645,9.9 -35.645,10.155 -35.645,10.3 -35.1,10.3 -35.1,11.3 -33.3,11.3 -33.3,7.571 -35.129,7.571
+3V3 on L1 (Signal) "+3V3_L01_P010" (solid, pour order 10): -25.755,7.945 -25.755,4.75 -27.775,4.75 -27.775,9.575 -26.596,9.575 -26.596,10.646 -26.204,10.646 -26.204,16.75 -24,16.75 -24,10.75 -24.4,10.75 -24.4,8.1 -25.755,8.1
+VCC on L1 (Signal) "+VCC_L01_P006" (solid, pour order 6): -57.5,18.2 cw(c-57.5,23.2) -62.5,23.2 cw(c-57.5,23.2) -57.5,28.2 cw(c-57.5,23.2) -52.5,23.2 cw(c-57.5,23.2)
PHASE_C on L1 (Signal) "PHASE_C_L01_P046" (solid, pour order 46): 37.3,-22.475 37.3,-26.7 39.8,-26.7 39.8,-22.6 50.609,-22.6 50.7,-14.8 28.6,-14.8 28.6,-15.525 29.1,-15.525 29.1,-16.125 28.6,-16.125 28.6,-16.825 29.1,-16.825 29.1,-17.425 28.5,-17.425 28.5,-18.125 29.05,-18.125 29.05,-19.625 28.5,-19.625 28.5,-20.825 29.05,-20.825 29.05,-23.279 30.144,-23.279 30.144,-23.425 29.05,-23.425 29.05,-24.549 30.144,-24.549 30.144,-24.7 29.05,-24.7 29.05,-25.813 30.144,-25.813 30.144,-25.971 29.05,-25.971 29.05,-27 33.4,-27 33.4,-22.475
GND on L1 (Signal) "GND_L01_P060" (solid, pour order 60): 24.754,-24.511 24.196,-24.511 24.196,-24.663 24.754,-24.663 24.754,-25.587 23.354,-25.587 23.354,-24.887 21.854,-24.887 21.854,-21.387 23.025,-21.387 23.025,-22.287 24.754,-22.287 24.754,-23.241 24.196,-23.241 24.196,-23.393 24.754,-23.393
GND on L1 (Signal) "GND_L01_P030" (solid, pour order 30): -16.238,17.388 -15.364,17.388 -15.364,17.188 -16.238,17.188 -16.238,8.088 -13.738,8.088 -13.738,18.588 -16.238,18.588
+5V on L1 (Signal) "+5V_L01_P057" (solid, pour order 57): -2.121,-18.6 -2.121,-18.873 -1.779,-18.873 -1.779,-18.6 -0.7,-18.6 -0.7,-20.5 -4.7,-20.5 -4.7,-18.6 -3.621,-18.6 -3.621,-18.873 -3.279,-18.873 -3.279,-18.6
GND on L1 (Signal) "GND_L01_P053" (solid, pour order 53): 33.946,-6.967 33.946,-12.227 33.946,-13.4 36.8,-13.4 36.8,-5.9 33.946,-5.9
PHASE_C on L1 (Signal) "PHASE_C_L01_P052" (solid, pour order 52): 17.7,-22.227 17.7,-23.027 20,-23.027 20,-24.927 21.3,-24.927 21.3,-21.427 20,-21.427 20,-22.227
+VCC on L1 (Signal) "+VCC_L01_P050" (solid, pour order 50): 21.373,-18.075 21.373,-17.849 21,-17.849 21,-16.475 21.373,-16.475 21.373,-15.775 20.6,-15.775 20.6,-14.075 22.2,-14.075 22.2,-14.742 22.289,-14.742 22.289,-13.741 23.006,-13.741 23.006,-13.375 24.6,-13.375 24.6,-14.429 23.006,-14.429 23.006,-14.575 24.6,-14.575 24.6,-15.675 23.006,-15.675 23.006,-15.851 24.6,-15.851 24.6,-16.969 23.006,-16.969 23.006,-17.135 24.6,-17.135 24.6,-18.075
PHASE_B on L1 (Signal) "PHASE_B_L01_P049" (solid, pour order 49): 17.7,-3.71 17.7,-4.51 20,-4.51 20,-6.41 21.3,-6.41 21.3,-2.91 20,-2.91 20,-3.71
GND on L1 (Signal) "GND_L01_P048" (solid, pour order 48): 24.6,-6.024 24.042,-6.024 24.042,-6.176 24.6,-6.176 24.6,-7.1 23.2,-7.1 23.2,-6.4 21.7,-6.4 21.7,-2.9 23.026,-2.9 23.026,-3.8 24.6,-3.8 24.6,-4.754 24.042,-4.754 24.042,-4.906 24.6,-4.906
+VCC on L1 (Signal) "+VCC_L01_P047" (solid, pour order 47): 24.52,3.894 23.006,3.894 23.006,4.059 24.52,4.059 24.52,5.095 23,5.095 23,4.775 22.3,4.775 22.3,3.725 21.851,3.725 21.851,4.395 20.52,4.395 20.52,2.695 21.35,2.695 21.35,1.995 20.92,1.995 20.92,0.621 21.35,0.621 21.35,0.395 24.52,0.395 24.52,1.335 23.006,1.335 23.006,1.506 24.52,1.506 24.52,2.624 23.006,2.624 23.006,2.795 24.52,2.795
PHASE_A on L1 (Signal) "PHASE_A_L01_P040" (solid, pour order 40): 29.05,11.054 30.144,11.054 30.144,11.212 29.05,11.212 29.05,12.325 30.144,12.325 30.144,12.476 29.05,12.476 29.05,13.6 30.144,13.6 30.144,13.746 29.05,13.746 29.05,16.2 28.5,16.2 28.5,17.4 29.05,17.4 29.05,18.9 28.5,18.9 28.5,19.6 29.1,19.6 29.1,20.2 28.6,20.2 28.6,20.9 29.1,20.9 29.1,21.5 28.6,21.5 28.6,22.2 50.7,22.2 50.61,14.525 33.4,14.525 33.4,10.1 29.05,10.1
PHASE_B on L1 (Signal) "PHASE_B_L01_P045" (solid, pour order 45): 37.3,-4 37.3,-8.2 39.8,-8.2 39.8,-4 50.61,-4 50.701,3.8 28.6,3.8 28.6,2.975 29.1,2.975 29.1,2.375 28.6,2.375 28.6,1.675 29.1,1.675 29.1,1.075 28.5,1.075 28.5,0.375 29.05,0.375 29.05,-1.125 28.5,-1.125 28.5,-2.325 29.05,-2.325 29.05,-4.779 30.144,-4.779 30.144,-4.925 29.05,-4.925 29.05,-6.049 30.144,-6.049 30.144,-6.2 29.05,-6.2 29.05,-7.312 30.144,-7.312 30.144,-7.471 29.05,-7.471 29.05,-8.425 33.4,-8.425 33.4,-4
PHASE_A on L1 (Signal) "PHASE_A_L01_P044" (solid, pour order 44): 17.7,14.8 17.7,14 20,14 20,12.1 21.3,12.1 21.3,15.6 20,15.6 20,14.8
+VCC on L1 (Signal) "+VCC_L01_P036" (solid, pour order 36): 21.373,18.9 21.373,19.126 21,19.126 21,20.5 21.373,20.5 21.373,21.2 20.6,21.2 20.6,22.9 22.2,22.9 22.2,22.233 22.289,22.233 22.289,23.234 23.006,23.234 23.006,23.6 24.6,23.6 24.6,22.546 23.006,22.546 23.006,22.4 24.6,22.4 24.6,21.3 23.006,21.3 23.006,21.124 24.6,21.124 24.6,20.006 23.006,20.006 23.006,19.84 24.6,19.84 24.6,18.9
GND on L1 (Signal) "GND_L01_P042" (solid, pour order 42): 24.6,12.476 24.042,12.476 24.042,12.324 24.6,12.324 24.6,11.4 23.2,11.4 23.2,12.1 21.7,12.1 21.7,15.6 23.026,15.6 23.026,14.7 24.6,14.7 24.6,13.746 24.042,13.746 24.042,13.594 24.6,13.594
PHASE_A on L1 (Signal) "PHASE_A_L01_P041" (solid, pour order 41): 37.3,10.4 39.8,10.4 39.8,14.7 37.3,14.7
GND on L1 (Signal) "GND_L01_P038" (solid, pour order 38): 33.946,11.633 33.946,6.373 33.946,5.2 36.8,5.2 36.8,12.7 33.946,12.7
GND on L1 (Signal) "GND_L01_P034" (solid, pour order 34): 18,28.579 18.9,28.579 18.9,28.8 18,28.8 18,29.7 20,29.7 20,27.5 18,27.5
GND on L1 (Signal) "GND_L01_P019" (solid, pour order 19): -13.5,4.6 -11.3,4.6 -11.3,6.4 -13.5,6.4
5V_BUCK_SW on L1 (Signal) "5V_BUCK_SW_L01_P018" (solid, pour order 18): -31.625,-8.29 -31.57,-8.29 -31.57,-9.52 -31.57,-9.8 -32.95,-9.8 -32.95,-10.6 -28.85,-10.6 -28.85,-7.2 -32.75,-7.2 -32.75,-8.1 -31.625,-8.1
+5V on L1 (Signal) "+5V_L01_P017" (solid, pour order 17): -25.679,-14.105 -25.679,-17.33 -27.863,-17.33 -27.863,-12.505 -26.684,-12.505 -26.684,-12.471 -26.59,-12.471 -26.59,-11.506 -26.292,-11.506 -26.292,-5.33 -24.088,-5.33 -24.088,-11.33 -24.488,-11.33 -24.488,-13.98 -25.679,-13.98
GND on L1 (Signal) "GND_L01_P016" (solid, pour order 16): -31.554,-11.75 -31.57,-11.75 -31.57,-11.83 -29.133,-11.83 -29.133,-17.35 -32.908,-17.35 -32.908,-10.8 -31.554,-10.8
+VCC on L1 (Signal) "+VCC_L01_P015" (solid, pour order 15): -35.43,-11.75 -35.725,-11.75 -35.725,-11.85 -35.725,-12.272 -36.8,-12.272 -36.8,-15.922 -35.205,-15.922 -35.205,-14.605 -35.125,-14.605 -35.125,-14.601 -33.35,-14.601 -33.35,-10.872 -35.15,-10.872 -35.15,-11.75
3V3_BUCK_SW on L1 (Signal) "3V3_BUCK_SW_L01_P014" (solid, pour order 14): -31.57,13.46 -31.57,12.58 -31.57,12.3 -32.9,12.3 -32.9,11.5 -28.8,11.5 -28.8,14.9 -32.7,14.9 -32.7,14 -31.8,14 -31.8,13.886 -31.64,13.886 -31.64,13.81 -31.57,13.81
GND on L1 (Signal) "GND_L01_P009" (solid, pour order 9): -31.57,10.35 -31.57,10.27 -29.225,10.27 -29.225,4.75 -33,4.75 -33,11.3 -31.646,11.3 -31.646,10.35
+VCC on L1 (Signal) "+VCC_L01_P007" (solid, pour order 7): -49.8,20.2 -56.4,20.2 -56.4,18.5 -49.8,18.5
+VBAT on L1 (Signal) "+VBAT_L01_P000" (solid, pour order 0): -49.25,20.25 -49.25,3.25 -40.6,3.25 -40.6,20.25
PHASE_C on L4 (Signal) "PHASE_C_L04_P056" (solid, pour order 56): 28.6,-14.9 28.6,-19.3 20,-19.3 20,-27 33.4,-27 33.4,-22.6 40.9,-22.6 40.9,-14.9 33.4,-14.9
PHASE_B on L4 (Signal) "PHASE_B_L04_P055" (solid, pour order 55): 28.6,3.8 28.6,-0.6 20,-0.6 20,-8.3 33.4,-8.3 33.4,-3.9 40.9,-3.9 40.9,3.8 33.4,3.8
PHASE_A on L4 (Signal) "PHASE_A_L04_P054" (solid, pour order 54): 28.6,22.2 28.6,17.8 20,17.8 20,10.1 33.4,10.1 33.4,14.5 40.9,14.5 40.9,22.2 33.4,22.2
+VCC on L3 (PWR) (split plane): 65.629,31.983 65.757,31.958 65.879,31.916 65.996,31.859 66.104,31.787 66.201,31.701 66.287,31.604 66.359,31.496 66.416,31.379 66.458,31.257 66.483,31.129 66.491,31.012 66.49,31 66.49,-31 66.491,-31.012 66.483,-31.129 66.458,-31.257 66.416,-31.379 66.359,-31.496 66.287,-31.604 66.201,-31.701 66.104,-31.787 65.996,-31.859 65.879,-31.916 65.757,-31.958 65.629,-31.983 65.512,-31.991 65.5,-31.99 -65.5,-31.99 -65.512,-31.991 -65.629,-31.983 -65.757,-31.958 -65.879,-31.916 -65.996,-31.859 -66.104,-31.787 -66.201,-31.701 -66.287,-31.604 -66.359,-31.496 -66.416,-31.379 -66.458,-31.257 -66.483,-31.129 -66.491,-31.012 -66.49,-31 -66.49,31 -66.491,31.012 -66.483,31.129 -66.458,31.257 -66.416,31.379 -66.359,31.496 -66.287,31.604 -66.201,31.701 -66.104,31.787 -65.996,31.859 -65.879,31.916 -65.757,31.958 -65.629,31.983 -65.512,31.991 -65.5,31.99 65.5,31.99 65.512,31.991
+VBAT on L3 (PWR) (split plane): -39.251,2.051 -50.749,2.051 -50.749,17.8 -50.749,21.449 -39.251,21.449
+5V on L3 (PWR) (split plane): -19.151,-7 -19.146,-7.039 -19.131,-7.076 -19.107,-7.107 -19.076,-7.131 -19.039,-7.146 -19,-7.151 -11.651,-7.151 -11.651,-10.5 -11.646,-10.539 -11.631,-10.576 -11.607,-10.607 -11.576,-10.631 -11.539,-10.646 -11.5,-10.651 4.849,-10.651 4.849,-11 4.849,-22.849 -30.599,-22.849 -30.599,-12.5 -30.604,-12.461 -30.619,-12.424 -30.643,-12.393 -30.674,-12.369 -30.711,-12.354 -30.75,-12.349 -35.849,-12.349 -35.849,-4.901 -31,-4.901 -30.961,-4.896 -30.924,-4.881 -30.893,-4.857 -30.869,-4.826 -30.854,-4.789 -30.849,-4.75 -30.849,0.099 -19.151,0.099
+3V3 on L3 (PWR) (split plane): 4.849,17 4.849,12.5 4.849,-10.349 -11.349,-10.349 -11.349,-7 -11.354,-6.961 -11.369,-6.924 -11.393,-6.893 -11.424,-6.869 -11.461,-6.854 -11.5,-6.849 -18.849,-6.849 -18.849,0.25 -18.854,0.289 -18.869,0.326 -18.893,0.357 -18.924,0.381 -18.961,0.396 -19,0.401 -30.849,0.401 -30.849,9.75 -30.854,9.789 -30.869,9.826 -30.893,9.857 -30.924,9.881 -30.961,9.896 -31,9.901 -35.849,9.901 -35.849,20.349 4.849,20.349
GND on L2 (GND) (split plane): 65.629,31.983 65.757,31.958 65.879,31.916 65.996,31.859 66.104,31.787 66.201,31.701 66.287,31.604 66.359,31.496 66.416,31.379 66.458,31.257 66.483,31.129 66.491,31.012 66.49,31 66.49,-31 66.491,-31.012 66.483,-31.129 66.458,-31.257 66.416,-31.379 66.359,-31.496 66.287,-31.604 66.201,-31.701 66.104,-31.787 65.996,-31.859 65.879,-31.916 65.757,-31.958 65.629,-31.983 65.512,-31.991 65.5,-31.99 -65.5,-31.99 -65.512,-31.991 -65.629,-31.983 -65.757,-31.958 -65.879,-31.916 -65.996,-31.859 -66.104,-31.787 -66.201,-31.701 -66.287,-31.604 -66.359,-31.496 -66.416,-31.379 -66.458,-31.257 -66.483,-31.129 -66.491,-31.012 -66.49,-31 -66.49,31 -66.491,31.012 -66.483,31.129 -66.458,31.257 -66.416,31.379 -66.359,31.496 -66.287,31.604 -66.201,31.701 -66.104,31.787 -65.996,31.859 -65.879,31.916 -65.757,31.958 -65.629,31.983 -65.512,31.991 -65.5,31.99 65.5,31.99 65.512,31.991

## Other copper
L3 (PWR) (plane layer: these items are gaps in the copper):
  lines w0.3: -31,0.25 -31,-4.75 -36,-4.75 -36,-12.5 -30.75,-12.5 -30.75,-23 -13.5,-23 5,-23 5,-11 5,-10.5 ; -31,0.25 -19,0.25 -19,-7 -11.5,-7 -11.5,-10.5 5,-10.5 ; -31,0.25 -31,9.75 -36,9.75 -36,20.5 5,20.5 5,17 5,12.5 5,-10.5 ; -50.9,1.9 -50.9,17.8 -50.9,21.6 -39.1,21.6 -39.1,1.9 -50.9,1.9

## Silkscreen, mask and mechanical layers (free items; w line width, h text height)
Top Overlay:
  lines w0.2: -48.99,-26.7 -48.99,-21.9 -22.79,-21.9 -22.79,-28.2 ; -31.3,-4.6 -23.3,-4.6 -23.3,-12.1 ; -31.2,17.6 -30.2,17.6 -23.3,17.6 -23.3,10.1 ; -30.99,27.6 -30.99,26.885 -30.99,21.5 -4.8,21.5 -4.8,21.8 -4.8,27.6 -4.79,27.6 ; -21.91,-26.6 -21.91,-21.9 4.29,-21.9 4.29,-26.6 ; -19.6,13.7 -19.6,7.6 -14.3,7.6 -14.1,7.6 ; -12.9,18 -8.5,18 -8.5,13.4 ; -6.75,10.25 -5,10.25 -2.25,10.25 -2.25,12.75 -6.5,12.75 -6.75,12.75 ; -3.693,27.6 -3.7,27.6 -3.7,21.5 4,21.5 4.7,21.5 4.7,27.6 ; 6.3,26.1 6.3,24.3 14.7,24.3 15.1,24.3 ; 12.2,-23.8 12.2,-18.5 19.8,-18.5 ; 12.2,-5.2 12.2,0 19.8,0 ; 12.2,13 12.2,18.5 20,18.5
  text "www.librethings.com" at -50.761,29.492 h1
  text "A" at 48.1,28.167 h1 r90
  text "COM" at 57,27.134 h1 r90
  text "PB9" at -29.8,26.8 h1 r270
  text "PB8" at -27.278,26.8 h1 r270
  text "PB7" at -24.756,26.8 h1 r270
  text "PB6" at -22.233,26.8 h1 r270
  text "PB5" at -19.711,26.8 h1 r270
  text "PB4" at -17.189,26.8 h1 r270
  text "GND" at -14.667,26.8 h1 r270
  text "GND" at -12.144,26.8 h1 r270
  text "3.3V" at -9.622,26.8 h1 r270
  text "5V" at -7.1,26.8 h1 r270
  text "SWO" at -2.3,26.8 h1 r270
  text "SWCLK" at 0.15,26.8 h1 r270
  text "SWIO" at 2.6,26.8 h1 r270
  text "USB" at 11.97,22.62 h1.1
  text "PHASE A" at 12.42,19.22 h1.1
  text "BOOT0" at -12.68,18.62 h1.1
  text "3.3V" at -30.98,18.12 h1.2
  text "HIGH" at -6.5,11 h1
  text "B" at 48.1,8.567 h1 r90
  text "COM" at 57,7.634 h1 r90
  text "RESET" at -18.98,5.92 h1.1
  text "PHASE B" at 12.42,0.57 h1.1
  text "5V" at -30.98,-4.08 h1.1
  text "librethings" at 9.316,-9.997 h2 r90
  text "C" at 48.1,-10.266 h1 r90
  text "COM" at 57,-11.333 h1 r90
  text "PHASE C" at 12.42,-17.93 h1.1
  text "(C) 2024" at -64.599,-20.175 h1.2
  text "PC15" at -47.8,-22.501 h1 r270
  text "PC14" at -45.233,-22.501 h1 r270
  text "PC13" at -42.667,-22.501 h1 r270
  text "PC10" at -40.1,-22.501 h1 r270
  text "EVB-A32S1-M" at -64.599,-22.55 h1.2
  text "PC5" at -37.533,-23.334 h1 r270
  text "PC4" at -34.967,-23.334 h1 r270
  text "PC3" at -32.4,-23.334 h1 r270
  text "PC2" at -29.833,-23.334 h1 r270
  text "PC0" at -24.7,-23.334 h1 r270
  text "PA0" at -20.7,-23.334 h1 r270
  text "PA2" at -15.7,-23.334 h1 r270
  text "PA3" at -13.2,-23.334 h1 r270
  text "PA4" at -10.7,-23.334 h1 r270
  text "PA5" at -8.2,-23.334 h1 r270
  text "PA6" at -5.7,-23.334 h1 r270
  text "PA7" at -3.2,-23.334 h1 r270
  text "PD2" at 2.4,-23.334 h1 r270
  text "PC1" at -27.267,-23.667 h1 r270
  text "PA1" at -18.2,-23.667 h1 r270
  text "REV 0.2" at -64.599,-24.925 h1.2
Bottom Overlay:
  drawing of 9 lines, arcs and shapes, not listed
  text "www.librethings.com" at 40.511,29.942 h1
  text "librethings" at -14.828,23.609 h2
  text "PHASE A" at 65.25,23.55 h1.5 r90
  text "12.6V" at -64.25,5.45 h1.5 r270
  text "PHASE B" at 65.25,4.3 h1.5 r90
  text "GND" at -64.25,-10.65 h1.5 r270
  text "PHASE C" at 65.25,-14.7 h1.5 r90
  text "(C) 2024" at -55.526,-20.075 h1.2
  text "EVB-A32S1-M" at -51.728,-22.45 h1.2
  text "REV 0.2" at -56.526,-24.825 h1.2
Mechanical 1:
  the board outline again, w0.1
